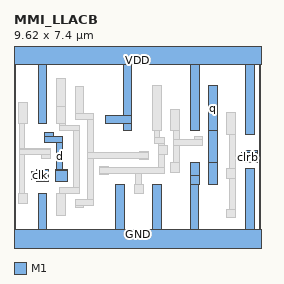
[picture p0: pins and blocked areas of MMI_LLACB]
MACRO MMI_LLACB
	CLASS CORE ;
	FOREIGN MMI_LLACB 0 0 ;
	SIZE 9.62 BY 7.4 ;
	SYMMETRY X Y ;
	SITE CORE1 ;
	PIN d
		DIRECTION input ;
		USE SIGNAL ;
		PORT
			LAYER M1 ;
			RECT 1.18 4.095 1.52 4.275 ;
			LAYER M1 ;
			RECT 1.18 3.865 1.89 4.095 ;
			LAYER M1 ;
			RECT 1.66 2.81 1.89 3.865 ;
			LAYER M1 ;
			RECT 1.62 2.8 2.075 2.81 ;
			LAYER M1 ;
			RECT 1.6 2.36 2.075 2.8 ;
		END
		AntennaGateArea 0.4968 ;
	END d
	PIN GND
		DIRECTION inout ;
		USE GROUND ;
		PORT
			LAYER M1 ;
			RECT 6.87 2.58 7.21 3.08 ;
			LAYER M1 ;
			RECT 0.94 0.5 1.28 1.875 ;
			LAYER M1 ;
			RECT 3.965 0.5 4.305 2.25 ;
			LAYER M1 ;
			RECT 5.405 0.5 5.745 2.25 ;
			LAYER M1 ;
			RECT 6.865 2.24 7.21 2.58 ;
			LAYER M1 ;
			RECT 6.865 0.5 7.205 2.24 ;
			LAYER M1 ;
			RECT 9.01 0.5 9.35 2.87 ;
			LAYER M1 ;
			RECT 0 -0.5 9.62 0.5 ;
		END
	END GND
	PIN q
		DIRECTION output ;
		USE SIGNAL ;
		PORT
			LAYER M1 ;
			RECT 7.59 4.335 7.93 6.095 ;
			LAYER M1 ;
			RECT 7.59 3.08 7.925 4.335 ;
			LAYER M1 ;
			RECT 7.59 2.24 7.93 3.08 ;
		END
		AntennaDiffArea 1.3248 ;
	END q
	PIN VDD
		DIRECTION inout ;
		USE POWER ;
		PORT
			LAYER M1 ;
			RECT 0 6.9 9.62 7.9 ;
			LAYER M1 ;
			RECT 0.94 4.605 1.28 6.9 ;
			LAYER M1 ;
			RECT 4.255 4.945 4.595 6.9 ;
			LAYER M1 ;
			RECT 3.57 4.605 4.595 4.945 ;
			LAYER M1 ;
			RECT 4.255 4.335 4.595 4.605 ;
			LAYER M1 ;
			RECT 6.87 4.335 7.21 6.9 ;
			LAYER M1 ;
			RECT 9.01 4.2 9.35 6.9 ;
		END
	END VDD
	PIN clk
		DIRECTION input ;
		USE CLOCK ;
		PORT
			LAYER M1 ;
			RECT 1.026 2.81 1.335 2.812 ;
			LAYER M1 ;
			RECT 0.88 2.755 1.335 2.81 ;
			LAYER M1 ;
			RECT 0.685 2.415 1.335 2.755 ;
			LAYER M1 ;
			RECT 0.875 2.365 1.335 2.415 ;
			LAYER M1 ;
			RECT 0.876 2.364 1.335 2.365 ;
		END
		AntennaGateArea 0.4896 ;
	END clk
	PIN clrb
		DIRECTION input ;
		USE SIGNAL ;
		PORT
			LAYER M1 ;
			RECT 9.02 3.47 9.475 3.56 ;
			LAYER M1 ;
			RECT 8.86 3.13 9.475 3.47 ;
			LAYER M1 ;
			RECT 9.02 3.114 9.475 3.13 ;
		END
		AntennaGateArea 0.2484 ;
	END clrb
	OBS
		LAYER M1 ;
		RECT 0.18 4.605 0.52 5.445 ;
		LAYER M1 ;
		RECT 1.66 5.29 2 6.365 ;
		LAYER M1 ;
		RECT 1.66 4.605 2.01 5.29 ;
		LAYER M1 ;
		RECT 2.38 5.015 2.72 6.065 ;
		LAYER M1 ;
		RECT 2.38 4.785 3.1 5.015 ;
		LAYER M1 ;
		RECT 0.195 3.635 0.425 4.605 ;
		LAYER M1 ;
		RECT 1.78 4.555 2.01 4.605 ;
		LAYER M1 ;
		RECT 1.78 4.325 2.535 4.555 ;
		LAYER M1 ;
		RECT 0.195 3.605 1.428 3.635 ;
		LAYER M1 ;
		RECT 0.195 3.405 1.43 3.605 ;
		LAYER M1 ;
		RECT 0.195 1.875 0.425 3.405 ;
		LAYER M1 ;
		RECT 1.09 3.265 1.43 3.405 ;
		LAYER M1 ;
		RECT 2.305 2.13 2.535 4.325 ;
		LAYER M1 ;
		RECT 1.77 1.9 2.535 2.13 ;
		LAYER M1 ;
		RECT 2.87 3.47 3.1 4.785 ;
		LAYER M1 ;
		RECT 5.405 4.335 5.745 6.095 ;
		LAYER M1 ;
		RECT 6.105 4.335 6.445 5.175 ;
		LAYER M1 ;
		RECT 5.455 4.075 5.685 4.335 ;
		LAYER M1 ;
		RECT 5.455 3.845 5.875 4.075 ;
		LAYER M1 ;
		RECT 5.645 3.74 5.875 3.845 ;
		LAYER M1 ;
		RECT 6.215 3.99 6.445 4.335 ;
		LAYER M1 ;
		RECT 7.015 3.99 7.355 4.1 ;
		LAYER M1 ;
		RECT 6.215 3.76 7.355 3.99 ;
		LAYER M1 ;
		RECT 4.905 3.47 5.245 3.535 ;
		LAYER M1 ;
		RECT 2.87 3.24 5.245 3.47 ;
		LAYER M1 ;
		RECT 1.77 1.875 2 1.9 ;
		LAYER M1 ;
		RECT 0.18 1.495 0.52 1.875 ;
		LAYER M1 ;
		RECT 1.66 1.035 2 1.875 ;
		LAYER M1 ;
		RECT 2.87 1.67 3.1 3.24 ;
		LAYER M1 ;
		RECT 4.905 3.195 5.245 3.24 ;
		LAYER M1 ;
		RECT 5.645 3.4 5.985 3.74 ;
		LAYER M1 ;
		RECT 3.335 2.89 3.675 2.95 ;
		LAYER M1 ;
		RECT 5.645 2.89 5.875 3.4 ;
		LAYER M1 ;
		RECT 6.215 3.085 6.445 3.76 ;
		LAYER M1 ;
		RECT 3.335 2.66 5.875 2.89 ;
		LAYER M1 ;
		RECT 6.105 2.705 6.445 3.085 ;
		LAYER M1 ;
		RECT 8.29 4.2 8.63 5.04 ;
		LAYER M1 ;
		RECT 3.335 2.61 3.675 2.66 ;
		LAYER M1 ;
		RECT 4.745 2.25 4.975 2.66 ;
		LAYER M1 ;
		RECT 2.38 1.44 3.1 1.67 ;
		LAYER M1 ;
		RECT 2.38 1.33 2.72 1.44 ;
		LAYER M1 ;
		RECT 4.685 1.87 5.025 2.25 ;
		LAYER M1 ;
		RECT 8.4 2.87 8.63 4.2 ;
		LAYER M1 ;
		RECT 8.29 2.49 8.63 2.87 ;
		LAYER M1 ;
		RECT 8.4 1.275 8.63 2.49 ;
		LAYER M1 ;
		RECT 8.29 0.935 8.63 1.275 ;
	END
END MMI_LLACB
